VERSION 5.8 ;
BUSBITCHARS "[]" ;
DIVIDERCHAR "/" ;
UNITS
    DATABASE MICRONS 1000 ;
END UNITS

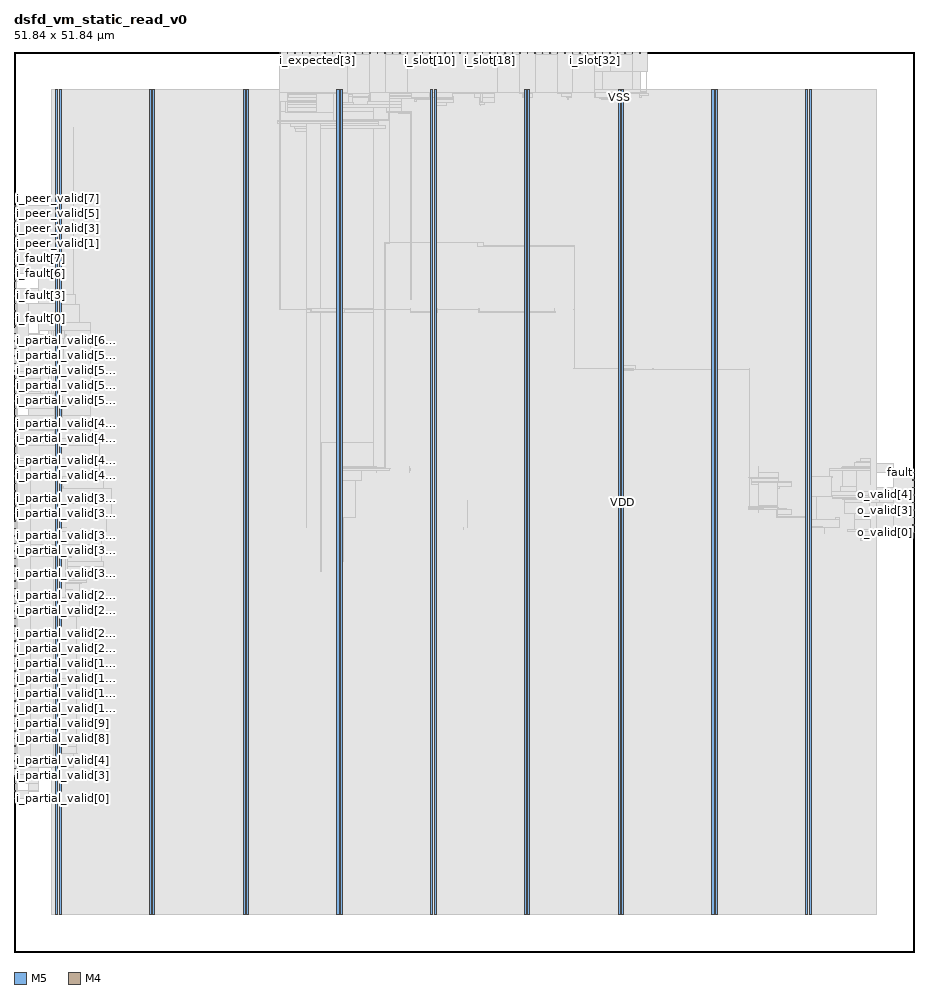
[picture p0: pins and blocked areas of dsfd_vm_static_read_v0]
MACRO dsfd_vm_static_read_v0
  FOREIGN dsfd_vm_static_read_v0 0 0 ;
  CLASS BLOCK ;
  SIZE 51.84 BY 51.84 ;
  PIN ck
    DIRECTION INPUT ;
    USE SIGNAL ;
    PORT
      LAYER M5 ;
        RECT  15.312 51.756 15.336 51.84 ;
    END
  END ck
  PIN fault
    DIRECTION OUTPUT ;
    USE SIGNAL ;
    PORT
      LAYER M4 ;
        RECT  51.756 27.6 51.84 27.624 ;
    END
  END fault
  PIN i_expected[0]
    DIRECTION INPUT ;
    USE SIGNAL ;
    PORT
      LAYER M5 ;
        RECT  16.176 51.756 16.2 51.84 ;
    END
  END i_expected[0]
  PIN i_expected[1]
    DIRECTION INPUT ;
    USE SIGNAL ;
    PORT
      LAYER M5 ;
        RECT  16.608 51.756 16.632 51.84 ;
    END
  END i_expected[1]
  PIN i_expected[2]
    DIRECTION INPUT ;
    USE SIGNAL ;
    PORT
      LAYER M5 ;
        RECT  17.04 51.756 17.064 51.84 ;
    END
  END i_expected[2]
  PIN i_expected[3]
    DIRECTION INPUT ;
    USE SIGNAL ;
    PORT
      LAYER M5 ;
        RECT  17.472 51.756 17.496 51.84 ;
    END
  END i_expected[3]
  PIN i_expected[4]
    DIRECTION INPUT ;
    USE SIGNAL ;
    PORT
      LAYER M5 ;
        RECT  17.904 51.756 17.928 51.84 ;
    END
  END i_expected[4]
  PIN i_expected[5]
    DIRECTION INPUT ;
    USE SIGNAL ;
    PORT
      LAYER M5 ;
        RECT  18.336 51.756 18.36 51.84 ;
    END
  END i_expected[5]
  PIN i_expected[6]
    DIRECTION INPUT ;
    USE SIGNAL ;
    PORT
      LAYER M5 ;
        RECT  18.768 51.756 18.792 51.84 ;
    END
  END i_expected[6]
  PIN i_expected[7]
    DIRECTION INPUT ;
    USE SIGNAL ;
    PORT
      LAYER M5 ;
        RECT  19.2 51.756 19.224 51.84 ;
    END
  END i_expected[7]
  PIN i_fault[0]
    DIRECTION INPUT ;
    USE SIGNAL ;
    PORT
      LAYER M4 ;
        RECT  0 36.48 0.084 36.504 ;
    END
  END i_fault[0]
  PIN i_fault[1]
    DIRECTION INPUT ;
    USE SIGNAL ;
    PORT
      LAYER M4 ;
        RECT  0 36.912 0.084 36.936 ;
    END
  END i_fault[1]
  PIN i_fault[2]
    DIRECTION INPUT ;
    USE SIGNAL ;
    PORT
      LAYER M4 ;
        RECT  0 37.344 0.084 37.368 ;
    END
  END i_fault[2]
  PIN i_fault[3]
    DIRECTION INPUT ;
    USE SIGNAL ;
    PORT
      LAYER M4 ;
        RECT  0 37.776 0.084 37.8 ;
    END
  END i_fault[3]
  PIN i_fault[4]
    DIRECTION INPUT ;
    USE SIGNAL ;
    PORT
      LAYER M4 ;
        RECT  0 38.208 0.084 38.232 ;
    END
  END i_fault[4]
  PIN i_fault[5]
    DIRECTION INPUT ;
    USE SIGNAL ;
    PORT
      LAYER M4 ;
        RECT  0 38.64 0.084 38.664 ;
    END
  END i_fault[5]
  PIN i_fault[6]
    DIRECTION INPUT ;
    USE SIGNAL ;
    PORT
      LAYER M4 ;
        RECT  0 39.072 0.084 39.096 ;
    END
  END i_fault[6]
  PIN i_fault[7]
    DIRECTION INPUT ;
    USE SIGNAL ;
    PORT
      LAYER M4 ;
        RECT  0 39.504 0.084 39.528 ;
    END
  END i_fault[7]
  PIN i_partial_valid[0]
    DIRECTION INPUT ;
    USE SIGNAL ;
    PORT
      LAYER M4 ;
        RECT  0 8.832 0.084 8.856 ;
    END
  END i_partial_valid[0]
  PIN i_partial_valid[10]
    DIRECTION INPUT ;
    USE SIGNAL ;
    PORT
      LAYER M4 ;
        RECT  0 13.152 0.084 13.176 ;
    END
  END i_partial_valid[10]
  PIN i_partial_valid[11]
    DIRECTION INPUT ;
    USE SIGNAL ;
    PORT
      LAYER M4 ;
        RECT  0 13.584 0.084 13.608 ;
    END
  END i_partial_valid[11]
  PIN i_partial_valid[12]
    DIRECTION INPUT ;
    USE SIGNAL ;
    PORT
      LAYER M4 ;
        RECT  0 14.016 0.084 14.04 ;
    END
  END i_partial_valid[12]
  PIN i_partial_valid[13]
    DIRECTION INPUT ;
    USE SIGNAL ;
    PORT
      LAYER M4 ;
        RECT  0 14.448 0.084 14.472 ;
    END
  END i_partial_valid[13]
  PIN i_partial_valid[14]
    DIRECTION INPUT ;
    USE SIGNAL ;
    PORT
      LAYER M4 ;
        RECT  0 14.88 0.084 14.904 ;
    END
  END i_partial_valid[14]
  PIN i_partial_valid[15]
    DIRECTION INPUT ;
    USE SIGNAL ;
    PORT
      LAYER M4 ;
        RECT  0 15.312 0.084 15.336 ;
    END
  END i_partial_valid[15]
  PIN i_partial_valid[16]
    DIRECTION INPUT ;
    USE SIGNAL ;
    PORT
      LAYER M4 ;
        RECT  0 15.744 0.084 15.768 ;
    END
  END i_partial_valid[16]
  PIN i_partial_valid[17]
    DIRECTION INPUT ;
    USE SIGNAL ;
    PORT
      LAYER M4 ;
        RECT  0 16.176 0.084 16.2 ;
    END
  END i_partial_valid[17]
  PIN i_partial_valid[18]
    DIRECTION INPUT ;
    USE SIGNAL ;
    PORT
      LAYER M4 ;
        RECT  0 16.608 0.084 16.632 ;
    END
  END i_partial_valid[18]
  PIN i_partial_valid[19]
    DIRECTION INPUT ;
    USE SIGNAL ;
    PORT
      LAYER M4 ;
        RECT  0 17.04 0.084 17.064 ;
    END
  END i_partial_valid[19]
  PIN i_partial_valid[1]
    DIRECTION INPUT ;
    USE SIGNAL ;
    PORT
      LAYER M4 ;
        RECT  0 9.264 0.084 9.288 ;
    END
  END i_partial_valid[1]
  PIN i_partial_valid[20]
    DIRECTION INPUT ;
    USE SIGNAL ;
    PORT
      LAYER M4 ;
        RECT  0 17.472 0.084 17.496 ;
    END
  END i_partial_valid[20]
  PIN i_partial_valid[21]
    DIRECTION INPUT ;
    USE SIGNAL ;
    PORT
      LAYER M4 ;
        RECT  0 17.904 0.084 17.928 ;
    END
  END i_partial_valid[21]
  PIN i_partial_valid[22]
    DIRECTION INPUT ;
    USE SIGNAL ;
    PORT
      LAYER M4 ;
        RECT  0 18.336 0.084 18.36 ;
    END
  END i_partial_valid[22]
  PIN i_partial_valid[23]
    DIRECTION INPUT ;
    USE SIGNAL ;
    PORT
      LAYER M4 ;
        RECT  0 18.768 0.084 18.792 ;
    END
  END i_partial_valid[23]
  PIN i_partial_valid[24]
    DIRECTION INPUT ;
    USE SIGNAL ;
    PORT
      LAYER M4 ;
        RECT  0 19.2 0.084 19.224 ;
    END
  END i_partial_valid[24]
  PIN i_partial_valid[25]
    DIRECTION INPUT ;
    USE SIGNAL ;
    PORT
      LAYER M4 ;
        RECT  0 19.632 0.084 19.656 ;
    END
  END i_partial_valid[25]
  PIN i_partial_valid[26]
    DIRECTION INPUT ;
    USE SIGNAL ;
    PORT
      LAYER M4 ;
        RECT  0 20.064 0.084 20.088 ;
    END
  END i_partial_valid[26]
  PIN i_partial_valid[27]
    DIRECTION INPUT ;
    USE SIGNAL ;
    PORT
      LAYER M4 ;
        RECT  0 20.496 0.084 20.52 ;
    END
  END i_partial_valid[27]
  PIN i_partial_valid[28]
    DIRECTION INPUT ;
    USE SIGNAL ;
    PORT
      LAYER M4 ;
        RECT  0 20.928 0.084 20.952 ;
    END
  END i_partial_valid[28]
  PIN i_partial_valid[29]
    DIRECTION INPUT ;
    USE SIGNAL ;
    PORT
      LAYER M4 ;
        RECT  0 21.36 0.084 21.384 ;
    END
  END i_partial_valid[29]
  PIN i_partial_valid[2]
    DIRECTION INPUT ;
    USE SIGNAL ;
    PORT
      LAYER M4 ;
        RECT  0 9.696 0.084 9.72 ;
    END
  END i_partial_valid[2]
  PIN i_partial_valid[30]
    DIRECTION INPUT ;
    USE SIGNAL ;
    PORT
      LAYER M4 ;
        RECT  0 21.792 0.084 21.816 ;
    END
  END i_partial_valid[30]
  PIN i_partial_valid[31]
    DIRECTION INPUT ;
    USE SIGNAL ;
    PORT
      LAYER M4 ;
        RECT  0 22.224 0.084 22.248 ;
    END
  END i_partial_valid[31]
  PIN i_partial_valid[32]
    DIRECTION INPUT ;
    USE SIGNAL ;
    PORT
      LAYER M4 ;
        RECT  0 22.656 0.084 22.68 ;
    END
  END i_partial_valid[32]
  PIN i_partial_valid[33]
    DIRECTION INPUT ;
    USE SIGNAL ;
    PORT
      LAYER M4 ;
        RECT  0 23.088 0.084 23.112 ;
    END
  END i_partial_valid[33]
  PIN i_partial_valid[34]
    DIRECTION INPUT ;
    USE SIGNAL ;
    PORT
      LAYER M4 ;
        RECT  0 23.52 0.084 23.544 ;
    END
  END i_partial_valid[34]
  PIN i_partial_valid[35]
    DIRECTION INPUT ;
    USE SIGNAL ;
    PORT
      LAYER M4 ;
        RECT  0 23.952 0.084 23.976 ;
    END
  END i_partial_valid[35]
  PIN i_partial_valid[36]
    DIRECTION INPUT ;
    USE SIGNAL ;
    PORT
      LAYER M4 ;
        RECT  0 24.384 0.084 24.408 ;
    END
  END i_partial_valid[36]
  PIN i_partial_valid[37]
    DIRECTION INPUT ;
    USE SIGNAL ;
    PORT
      LAYER M4 ;
        RECT  0 24.816 0.084 24.84 ;
    END
  END i_partial_valid[37]
  PIN i_partial_valid[38]
    DIRECTION INPUT ;
    USE SIGNAL ;
    PORT
      LAYER M4 ;
        RECT  0 25.248 0.084 25.272 ;
    END
  END i_partial_valid[38]
  PIN i_partial_valid[39]
    DIRECTION INPUT ;
    USE SIGNAL ;
    PORT
      LAYER M4 ;
        RECT  0 25.68 0.084 25.704 ;
    END
  END i_partial_valid[39]
  PIN i_partial_valid[3]
    DIRECTION INPUT ;
    USE SIGNAL ;
    PORT
      LAYER M4 ;
        RECT  0 10.128 0.084 10.152 ;
    END
  END i_partial_valid[3]
  PIN i_partial_valid[40]
    DIRECTION INPUT ;
    USE SIGNAL ;
    PORT
      LAYER M4 ;
        RECT  0 26.112 0.084 26.136 ;
    END
  END i_partial_valid[40]
  PIN i_partial_valid[41]
    DIRECTION INPUT ;
    USE SIGNAL ;
    PORT
      LAYER M4 ;
        RECT  0 26.544 0.084 26.568 ;
    END
  END i_partial_valid[41]
  PIN i_partial_valid[42]
    DIRECTION INPUT ;
    USE SIGNAL ;
    PORT
      LAYER M4 ;
        RECT  0 26.976 0.084 27 ;
    END
  END i_partial_valid[42]
  PIN i_partial_valid[43]
    DIRECTION INPUT ;
    USE SIGNAL ;
    PORT
      LAYER M4 ;
        RECT  0 27.408 0.084 27.432 ;
    END
  END i_partial_valid[43]
  PIN i_partial_valid[44]
    DIRECTION INPUT ;
    USE SIGNAL ;
    PORT
      LAYER M4 ;
        RECT  0 27.84 0.084 27.864 ;
    END
  END i_partial_valid[44]
  PIN i_partial_valid[45]
    DIRECTION INPUT ;
    USE SIGNAL ;
    PORT
      LAYER M4 ;
        RECT  0 28.272 0.084 28.296 ;
    END
  END i_partial_valid[45]
  PIN i_partial_valid[46]
    DIRECTION INPUT ;
    USE SIGNAL ;
    PORT
      LAYER M4 ;
        RECT  0 28.704 0.084 28.728 ;
    END
  END i_partial_valid[46]
  PIN i_partial_valid[47]
    DIRECTION INPUT ;
    USE SIGNAL ;
    PORT
      LAYER M4 ;
        RECT  0 29.136 0.084 29.16 ;
    END
  END i_partial_valid[47]
  PIN i_partial_valid[48]
    DIRECTION INPUT ;
    USE SIGNAL ;
    PORT
      LAYER M4 ;
        RECT  0 29.568 0.084 29.592 ;
    END
  END i_partial_valid[48]
  PIN i_partial_valid[49]
    DIRECTION INPUT ;
    USE SIGNAL ;
    PORT
      LAYER M4 ;
        RECT  0 30 0.084 30.024 ;
    END
  END i_partial_valid[49]
  PIN i_partial_valid[4]
    DIRECTION INPUT ;
    USE SIGNAL ;
    PORT
      LAYER M4 ;
        RECT  0 10.56 0.084 10.584 ;
    END
  END i_partial_valid[4]
  PIN i_partial_valid[50]
    DIRECTION INPUT ;
    USE SIGNAL ;
    PORT
      LAYER M4 ;
        RECT  0 30.432 0.084 30.456 ;
    END
  END i_partial_valid[50]
  PIN i_partial_valid[51]
    DIRECTION INPUT ;
    USE SIGNAL ;
    PORT
      LAYER M4 ;
        RECT  0 30.864 0.084 30.888 ;
    END
  END i_partial_valid[51]
  PIN i_partial_valid[52]
    DIRECTION INPUT ;
    USE SIGNAL ;
    PORT
      LAYER M4 ;
        RECT  0 31.296 0.084 31.32 ;
    END
  END i_partial_valid[52]
  PIN i_partial_valid[53]
    DIRECTION INPUT ;
    USE SIGNAL ;
    PORT
      LAYER M4 ;
        RECT  0 31.728 0.084 31.752 ;
    END
  END i_partial_valid[53]
  PIN i_partial_valid[54]
    DIRECTION INPUT ;
    USE SIGNAL ;
    PORT
      LAYER M4 ;
        RECT  0 32.16 0.084 32.184 ;
    END
  END i_partial_valid[54]
  PIN i_partial_valid[55]
    DIRECTION INPUT ;
    USE SIGNAL ;
    PORT
      LAYER M4 ;
        RECT  0 32.592 0.084 32.616 ;
    END
  END i_partial_valid[55]
  PIN i_partial_valid[56]
    DIRECTION INPUT ;
    USE SIGNAL ;
    PORT
      LAYER M4 ;
        RECT  0 33.024 0.084 33.048 ;
    END
  END i_partial_valid[56]
  PIN i_partial_valid[57]
    DIRECTION INPUT ;
    USE SIGNAL ;
    PORT
      LAYER M4 ;
        RECT  0 33.456 0.084 33.48 ;
    END
  END i_partial_valid[57]
  PIN i_partial_valid[58]
    DIRECTION INPUT ;
    USE SIGNAL ;
    PORT
      LAYER M4 ;
        RECT  0 33.888 0.084 33.912 ;
    END
  END i_partial_valid[58]
  PIN i_partial_valid[59]
    DIRECTION INPUT ;
    USE SIGNAL ;
    PORT
      LAYER M4 ;
        RECT  0 34.32 0.084 34.344 ;
    END
  END i_partial_valid[59]
  PIN i_partial_valid[5]
    DIRECTION INPUT ;
    USE SIGNAL ;
    PORT
      LAYER M4 ;
        RECT  0 10.992 0.084 11.016 ;
    END
  END i_partial_valid[5]
  PIN i_partial_valid[60]
    DIRECTION INPUT ;
    USE SIGNAL ;
    PORT
      LAYER M4 ;
        RECT  0 34.752 0.084 34.776 ;
    END
  END i_partial_valid[60]
  PIN i_partial_valid[61]
    DIRECTION INPUT ;
    USE SIGNAL ;
    PORT
      LAYER M4 ;
        RECT  0 35.184 0.084 35.208 ;
    END
  END i_partial_valid[61]
  PIN i_partial_valid[62]
    DIRECTION INPUT ;
    USE SIGNAL ;
    PORT
      LAYER M4 ;
        RECT  0 35.616 0.084 35.64 ;
    END
  END i_partial_valid[62]
  PIN i_partial_valid[63]
    DIRECTION INPUT ;
    USE SIGNAL ;
    PORT
      LAYER M4 ;
        RECT  0 36.048 0.084 36.072 ;
    END
  END i_partial_valid[63]
  PIN i_partial_valid[6]
    DIRECTION INPUT ;
    USE SIGNAL ;
    PORT
      LAYER M4 ;
        RECT  0 11.424 0.084 11.448 ;
    END
  END i_partial_valid[6]
  PIN i_partial_valid[7]
    DIRECTION INPUT ;
    USE SIGNAL ;
    PORT
      LAYER M4 ;
        RECT  0 11.856 0.084 11.88 ;
    END
  END i_partial_valid[7]
  PIN i_partial_valid[8]
    DIRECTION INPUT ;
    USE SIGNAL ;
    PORT
      LAYER M4 ;
        RECT  0 12.288 0.084 12.312 ;
    END
  END i_partial_valid[8]
  PIN i_partial_valid[9]
    DIRECTION INPUT ;
    USE SIGNAL ;
    PORT
      LAYER M4 ;
        RECT  0 12.72 0.084 12.744 ;
    END
  END i_partial_valid[9]
  PIN i_peer_valid[0]
    DIRECTION INPUT ;
    USE SIGNAL ;
    PORT
      LAYER M4 ;
        RECT  0 39.936 0.084 39.96 ;
    END
  END i_peer_valid[0]
  PIN i_peer_valid[1]
    DIRECTION INPUT ;
    USE SIGNAL ;
    PORT
      LAYER M4 ;
        RECT  0 40.368 0.084 40.392 ;
    END
  END i_peer_valid[1]
  PIN i_peer_valid[2]
    DIRECTION INPUT ;
    USE SIGNAL ;
    PORT
      LAYER M4 ;
        RECT  0 40.8 0.084 40.824 ;
    END
  END i_peer_valid[2]
  PIN i_peer_valid[3]
    DIRECTION INPUT ;
    USE SIGNAL ;
    PORT
      LAYER M4 ;
        RECT  0 41.232 0.084 41.256 ;
    END
  END i_peer_valid[3]
  PIN i_peer_valid[4]
    DIRECTION INPUT ;
    USE SIGNAL ;
    PORT
      LAYER M4 ;
        RECT  0 41.664 0.084 41.688 ;
    END
  END i_peer_valid[4]
  PIN i_peer_valid[5]
    DIRECTION INPUT ;
    USE SIGNAL ;
    PORT
      LAYER M4 ;
        RECT  0 42.096 0.084 42.12 ;
    END
  END i_peer_valid[5]
  PIN i_peer_valid[6]
    DIRECTION INPUT ;
    USE SIGNAL ;
    PORT
      LAYER M4 ;
        RECT  0 42.528 0.084 42.552 ;
    END
  END i_peer_valid[6]
  PIN i_peer_valid[7]
    DIRECTION INPUT ;
    USE SIGNAL ;
    PORT
      LAYER M4 ;
        RECT  0 42.96 0.084 42.984 ;
    END
  END i_peer_valid[7]
  PIN i_slot[0]
    DIRECTION INPUT ;
    USE SIGNAL ;
    PORT
      LAYER M5 ;
        RECT  19.632 51.756 19.656 51.84 ;
    END
  END i_slot[0]
  PIN i_slot[10]
    DIRECTION INPUT ;
    USE SIGNAL ;
    PORT
      LAYER M5 ;
        RECT  23.952 51.756 23.976 51.84 ;
    END
  END i_slot[10]
  PIN i_slot[11]
    DIRECTION INPUT ;
    USE SIGNAL ;
    PORT
      LAYER M5 ;
        RECT  24.384 51.756 24.408 51.84 ;
    END
  END i_slot[11]
  PIN i_slot[12]
    DIRECTION INPUT ;
    USE SIGNAL ;
    PORT
      LAYER M5 ;
        RECT  24.816 51.756 24.84 51.84 ;
    END
  END i_slot[12]
  PIN i_slot[13]
    DIRECTION INPUT ;
    USE SIGNAL ;
    PORT
      LAYER M5 ;
        RECT  25.248 51.756 25.272 51.84 ;
    END
  END i_slot[13]
  PIN i_slot[14]
    DIRECTION INPUT ;
    USE SIGNAL ;
    PORT
      LAYER M5 ;
        RECT  25.68 51.756 25.704 51.84 ;
    END
  END i_slot[14]
  PIN i_slot[15]
    DIRECTION INPUT ;
    USE SIGNAL ;
    PORT
      LAYER M5 ;
        RECT  26.112 51.756 26.136 51.84 ;
    END
  END i_slot[15]
  PIN i_slot[16]
    DIRECTION INPUT ;
    USE SIGNAL ;
    PORT
      LAYER M5 ;
        RECT  26.544 51.756 26.568 51.84 ;
    END
  END i_slot[16]
  PIN i_slot[17]
    DIRECTION INPUT ;
    USE SIGNAL ;
    PORT
      LAYER M5 ;
        RECT  26.976 51.756 27 51.84 ;
    END
  END i_slot[17]
  PIN i_slot[18]
    DIRECTION INPUT ;
    USE SIGNAL ;
    PORT
      LAYER M5 ;
        RECT  27.408 51.756 27.432 51.84 ;
    END
  END i_slot[18]
  PIN i_slot[19]
    DIRECTION INPUT ;
    USE SIGNAL ;
    PORT
      LAYER M5 ;
        RECT  27.84 51.756 27.864 51.84 ;
    END
  END i_slot[19]
  PIN i_slot[1]
    DIRECTION INPUT ;
    USE SIGNAL ;
    PORT
      LAYER M5 ;
        RECT  20.064 51.756 20.088 51.84 ;
    END
  END i_slot[1]
  PIN i_slot[20]
    DIRECTION INPUT ;
    USE SIGNAL ;
    PORT
      LAYER M5 ;
        RECT  28.272 51.756 28.296 51.84 ;
    END
  END i_slot[20]
  PIN i_slot[21]
    DIRECTION INPUT ;
    USE SIGNAL ;
    PORT
      LAYER M5 ;
        RECT  28.704 51.756 28.728 51.84 ;
    END
  END i_slot[21]
  PIN i_slot[22]
    DIRECTION INPUT ;
    USE SIGNAL ;
    PORT
      LAYER M5 ;
        RECT  29.136 51.756 29.16 51.84 ;
    END
  END i_slot[22]
  PIN i_slot[23]
    DIRECTION INPUT ;
    USE SIGNAL ;
    PORT
      LAYER M5 ;
        RECT  29.568 51.756 29.592 51.84 ;
    END
  END i_slot[23]
  PIN i_slot[24]
    DIRECTION INPUT ;
    USE SIGNAL ;
    PORT
      LAYER M5 ;
        RECT  30 51.756 30.024 51.84 ;
    END
  END i_slot[24]
  PIN i_slot[25]
    DIRECTION INPUT ;
    USE SIGNAL ;
    PORT
      LAYER M5 ;
        RECT  30.432 51.756 30.456 51.84 ;
    END
  END i_slot[25]
  PIN i_slot[26]
    DIRECTION INPUT ;
    USE SIGNAL ;
    PORT
      LAYER M5 ;
        RECT  30.864 51.756 30.888 51.84 ;
    END
  END i_slot[26]
  PIN i_slot[27]
    DIRECTION INPUT ;
    USE SIGNAL ;
    PORT
      LAYER M5 ;
        RECT  31.296 51.756 31.32 51.84 ;
    END
  END i_slot[27]
  PIN i_slot[28]
    DIRECTION INPUT ;
    USE SIGNAL ;
    PORT
      LAYER M5 ;
        RECT  31.728 51.756 31.752 51.84 ;
    END
  END i_slot[28]
  PIN i_slot[29]
    DIRECTION INPUT ;
    USE SIGNAL ;
    PORT
      LAYER M5 ;
        RECT  32.16 51.756 32.184 51.84 ;
    END
  END i_slot[29]
  PIN i_slot[2]
    DIRECTION INPUT ;
    USE SIGNAL ;
    PORT
      LAYER M5 ;
        RECT  20.496 51.756 20.52 51.84 ;
    END
  END i_slot[2]
  PIN i_slot[30]
    DIRECTION INPUT ;
    USE SIGNAL ;
    PORT
      LAYER M5 ;
        RECT  32.592 51.756 32.616 51.84 ;
    END
  END i_slot[30]
  PIN i_slot[31]
    DIRECTION INPUT ;
    USE SIGNAL ;
    PORT
      LAYER M5 ;
        RECT  33.024 51.756 33.048 51.84 ;
    END
  END i_slot[31]
  PIN i_slot[32]
    DIRECTION INPUT ;
    USE SIGNAL ;
    PORT
      LAYER M5 ;
        RECT  33.456 51.756 33.48 51.84 ;
    END
  END i_slot[32]
  PIN i_slot[33]
    DIRECTION INPUT ;
    USE SIGNAL ;
    PORT
      LAYER M5 ;
        RECT  33.888 51.756 33.912 51.84 ;
    END
  END i_slot[33]
  PIN i_slot[34]
    DIRECTION INPUT ;
    USE SIGNAL ;
    PORT
      LAYER M5 ;
        RECT  34.32 51.756 34.344 51.84 ;
    END
  END i_slot[34]
  PIN i_slot[35]
    DIRECTION INPUT ;
    USE SIGNAL ;
    PORT
      LAYER M5 ;
        RECT  34.752 51.756 34.776 51.84 ;
    END
  END i_slot[35]
  PIN i_slot[36]
    DIRECTION INPUT ;
    USE SIGNAL ;
    PORT
      LAYER M5 ;
        RECT  35.184 51.756 35.208 51.84 ;
    END
  END i_slot[36]
  PIN i_slot[37]
    DIRECTION INPUT ;
    USE SIGNAL ;
    PORT
      LAYER M5 ;
        RECT  35.616 51.756 35.64 51.84 ;
    END
  END i_slot[37]
  PIN i_slot[38]
    DIRECTION INPUT ;
    USE SIGNAL ;
    PORT
      LAYER M5 ;
        RECT  36.048 51.756 36.072 51.84 ;
    END
  END i_slot[38]
  PIN i_slot[39]
    DIRECTION INPUT ;
    USE SIGNAL ;
    PORT
      LAYER M5 ;
        RECT  36.48 51.756 36.504 51.84 ;
    END
  END i_slot[39]
  PIN i_slot[3]
    DIRECTION INPUT ;
    USE SIGNAL ;
    PORT
      LAYER M5 ;
        RECT  20.928 51.756 20.952 51.84 ;
    END
  END i_slot[3]
  PIN i_slot[4]
    DIRECTION INPUT ;
    USE SIGNAL ;
    PORT
      LAYER M5 ;
        RECT  21.36 51.756 21.384 51.84 ;
    END
  END i_slot[4]
  PIN i_slot[5]
    DIRECTION INPUT ;
    USE SIGNAL ;
    PORT
      LAYER M5 ;
        RECT  21.792 51.756 21.816 51.84 ;
    END
  END i_slot[5]
  PIN i_slot[6]
    DIRECTION INPUT ;
    USE SIGNAL ;
    PORT
      LAYER M5 ;
        RECT  22.224 51.756 22.248 51.84 ;
    END
  END i_slot[6]
  PIN i_slot[7]
    DIRECTION INPUT ;
    USE SIGNAL ;
    PORT
      LAYER M5 ;
        RECT  22.656 51.756 22.68 51.84 ;
    END
  END i_slot[7]
  PIN i_slot[8]
    DIRECTION INPUT ;
    USE SIGNAL ;
    PORT
      LAYER M5 ;
        RECT  23.088 51.756 23.112 51.84 ;
    END
  END i_slot[8]
  PIN i_slot[9]
    DIRECTION INPUT ;
    USE SIGNAL ;
    PORT
      LAYER M5 ;
        RECT  23.52 51.756 23.544 51.84 ;
    END
  END i_slot[9]
  PIN o_valid[0]
    DIRECTION OUTPUT ;
    USE SIGNAL ;
    PORT
      LAYER M4 ;
        RECT  51.756 24.144 51.84 24.168 ;
    END
  END o_valid[0]
  PIN o_valid[1]
    DIRECTION OUTPUT ;
    USE SIGNAL ;
    PORT
      LAYER M4 ;
        RECT  51.756 24.576 51.84 24.6 ;
    END
  END o_valid[1]
  PIN o_valid[2]
    DIRECTION OUTPUT ;
    USE SIGNAL ;
    PORT
      LAYER M4 ;
        RECT  51.756 25.008 51.84 25.032 ;
    END
  END o_valid[2]
  PIN o_valid[3]
    DIRECTION OUTPUT ;
    USE SIGNAL ;
    PORT
      LAYER M4 ;
        RECT  51.756 25.44 51.84 25.464 ;
    END
  END o_valid[3]
  PIN o_valid[4]
    DIRECTION OUTPUT ;
    USE SIGNAL ;
    PORT
      LAYER M4 ;
        RECT  51.756 25.872 51.84 25.896 ;
    END
  END o_valid[4]
  PIN o_valid[5]
    DIRECTION OUTPUT ;
    USE SIGNAL ;
    PORT
      LAYER M4 ;
        RECT  51.756 26.304 51.84 26.328 ;
    END
  END o_valid[5]
  PIN o_valid[6]
    DIRECTION OUTPUT ;
    USE SIGNAL ;
    PORT
      LAYER M4 ;
        RECT  51.756 26.736 51.84 26.76 ;
    END
  END o_valid[6]
  PIN o_valid[7]
    DIRECTION OUTPUT ;
    USE SIGNAL ;
    PORT
      LAYER M4 ;
        RECT  51.756 27.168 51.84 27.192 ;
    END
  END o_valid[7]
  PIN rst_n
    DIRECTION INPUT ;
    USE SIGNAL ;
    PORT
      LAYER M5 ;
        RECT  15.744 51.756 15.768 51.84 ;
    END
  END rst_n
  PIN VDD
    DIRECTION INOUT ;
    USE POWER ;
    PORT
      LAYER M5 ;
        RECT  45.792 2.151 45.912 49.689 ;
        RECT  40.392 2.151 40.512 49.689 ;
        RECT  34.992 2.151 35.112 49.689 ;
        RECT  29.592 2.151 29.712 49.689 ;
        RECT  24.192 2.151 24.312 49.689 ;
        RECT  18.792 2.151 18.912 49.689 ;
        RECT  13.392 2.151 13.512 49.689 ;
        RECT  7.992 2.151 8.112 49.689 ;
        RECT  2.592 2.151 2.712 49.689 ;
    END
  END VDD
  PIN VSS
    DIRECTION INOUT ;
    USE GROUND ;
    PORT
      LAYER M5 ;
        RECT  45.6 2.137 45.72 49.703 ;
        RECT  40.2 2.137 40.32 49.703 ;
        RECT  34.8 2.137 34.92 49.703 ;
        RECT  29.4 2.137 29.52 49.703 ;
        RECT  24 2.137 24.12 49.703 ;
        RECT  18.6 2.137 18.72 49.703 ;
        RECT  13.2 2.137 13.32 49.703 ;
        RECT  7.8 2.137 7.92 49.703 ;
        RECT  2.4 2.137 2.52 49.703 ;
    END
  END VSS
  # OT_OBS_CLOSED layer=M5 d_um=1.536 added=32
  OBS
    LAYER RVTN ;
     RECT  2.16 2.16 49.68 2.295 ;
     RECT  2.16 2.565 49.68 2.835 ;
     RECT  2.16 3.105 49.68 3.375 ;
     RECT  2.16 3.645 49.68 3.915 ;
     RECT  2.16 4.185 49.68 4.455 ;
     RECT  2.16 4.725 49.68 4.995 ;
     RECT  2.16 5.265 49.68 5.535 ;
     RECT  2.16 5.805 49.68 6.075 ;
     RECT  2.16 6.345 49.68 6.615 ;
     RECT  2.16 6.885 49.68 7.155 ;
     RECT  2.16 7.425 49.68 7.695 ;
     RECT  2.16 7.965 49.68 8.235 ;
     RECT  2.16 8.505 49.68 8.775 ;
     RECT  2.16 9.045 49.68 9.315 ;
     RECT  2.16 9.585 49.68 9.855 ;
     RECT  2.16 10.125 49.68 10.395 ;
     RECT  2.16 10.665 49.68 10.935 ;
     RECT  2.16 11.205 49.68 11.475 ;
     RECT  2.16 11.745 49.68 12.015 ;
     RECT  2.16 12.285 49.68 12.555 ;
     RECT  2.16 12.825 49.68 13.095 ;
     RECT  2.16 13.365 49.68 13.635 ;
     RECT  2.16 13.905 49.68 14.175 ;
     RECT  2.16 14.445 49.68 14.715 ;
     RECT  2.16 14.985 49.68 15.255 ;
     RECT  2.16 15.525 49.68 15.795 ;
     RECT  2.16 16.065 49.68 16.335 ;
     RECT  2.16 16.605 49.68 16.875 ;
     RECT  2.16 17.145 49.68 17.415 ;
     RECT  2.16 17.685 49.68 17.955 ;
     RECT  2.16 18.225 49.68 18.495 ;
     RECT  2.16 18.765 49.68 19.035 ;
     RECT  2.16 19.305 49.68 19.575 ;
     RECT  2.16 19.845 49.68 20.115 ;
     RECT  2.16 20.385 49.68 20.655 ;
     RECT  2.16 20.925 49.68 21.195 ;
     RECT  2.16 21.465 49.68 21.735 ;
     RECT  2.16 22.005 49.68 22.275 ;
     RECT  2.16 22.545 49.68 22.815 ;
     RECT  2.16 23.085 49.68 23.355 ;
     RECT  2.16 23.625 49.68 23.895 ;
     RECT  2.16 24.165 49.68 24.435 ;
     RECT  2.16 24.705 49.68 24.975 ;
     RECT  2.16 25.245 49.68 25.515 ;
     RECT  2.16 25.785 49.68 26.055 ;
     RECT  2.16 26.325 49.68 26.595 ;
     RECT  2.16 26.865 49.68 27.135 ;
     RECT  2.16 27.405 49.68 27.675 ;
     RECT  2.16 27.945 49.68 28.215 ;
     RECT  2.16 28.485 49.68 28.755 ;
     RECT  2.16 29.025 49.68 29.295 ;
     RECT  2.16 29.565 49.68 29.835 ;
     RECT  2.16 30.105 49.68 30.375 ;
     RECT  2.16 30.645 49.68 30.915 ;
     RECT  2.16 31.185 49.68 31.455 ;
     RECT  2.16 31.725 49.68 31.995 ;
     RECT  2.16 32.265 49.68 32.535 ;
     RECT  2.16 32.805 49.68 33.075 ;
     RECT  2.16 33.345 49.68 33.615 ;
     RECT  2.16 33.885 49.68 34.155 ;
     RECT  2.16 34.425 49.68 34.695 ;
     RECT  2.16 34.965 49.68 35.235 ;
     RECT  2.16 35.505 49.68 35.775 ;
     RECT  2.16 36.045 49.68 36.315 ;
     RECT  2.16 36.585 49.68 36.855 ;
     RECT  2.16 37.125 49.68 37.395 ;
     RECT  2.16 37.665 49.68 37.935 ;
     RECT  2.16 38.205 49.68 38.475 ;
     RECT  2.16 38.745 49.68 39.015 ;
     RECT  2.16 39.285 49.68 39.555 ;
     RECT  2.16 39.825 49.68 40.095 ;
     RECT  2.16 40.365 49.68 40.635 ;
     RECT  2.16 40.905 49.68 41.175 ;
     RECT  2.16 41.445 49.68 41.715 ;
     RECT  2.16 41.985 49.68 42.255 ;
     RECT  2.16 42.525 49.68 42.795 ;
     RECT  2.16 43.065 49.68 43.335 ;
     RECT  2.16 43.605 49.68 43.875 ;
     RECT  2.16 44.145 49.68 44.415 ;
     RECT  2.16 44.685 49.68 44.955 ;
     RECT  2.16 45.225 49.68 45.495 ;
     RECT  2.16 45.765 49.68 46.035 ;
     RECT  2.16 46.305 49.68 46.575 ;
     RECT  2.16 46.845 49.68 47.115 ;
     RECT  2.16 47.385 49.68 47.655 ;
     RECT  2.16 47.925 49.68 48.195 ;
     RECT  2.16 48.465 49.68 48.735 ;
     RECT  2.16 49.005 49.68 49.275 ;
     RECT  2.16 49.545 49.68 49.68 ;
    LAYER RVTP ;
     RECT  2.16 2.295 49.68 2.565 ;
     RECT  2.16 2.835 49.68 3.105 ;
     RECT  2.16 3.375 49.68 3.645 ;
     RECT  2.16 3.915 49.68 4.185 ;
     RECT  2.16 4.455 49.68 4.725 ;
     RECT  2.16 4.995 49.68 5.265 ;
     RECT  2.16 5.535 49.68 5.805 ;
     RECT  2.16 6.075 49.68 6.345 ;
     RECT  2.16 6.615 49.68 6.885 ;
     RECT  2.16 7.155 49.68 7.425 ;
     RECT  2.16 7.695 49.68 7.965 ;
     RECT  2.16 8.235 49.68 8.505 ;
     RECT  2.16 8.775 49.68 9.045 ;
     RECT  2.16 9.315 49.68 9.585 ;
     RECT  2.16 9.855 49.68 10.125 ;
     RECT  2.16 10.395 49.68 10.665 ;
     RECT  2.16 10.935 49.68 11.205 ;
     RECT  2.16 11.475 49.68 11.745 ;
     RECT  2.16 12.015 49.68 12.285 ;
     RECT  2.16 12.555 49.68 12.825 ;
     RECT  2.16 13.095 49.68 13.365 ;
     RECT  2.16 13.635 49.68 13.905 ;
     RECT  2.16 14.175 49.68 14.445 ;
     RECT  2.16 14.715 49.68 14.985 ;
     RECT  2.16 15.255 49.68 15.525 ;
     RECT  2.16 15.795 49.68 16.065 ;
     RECT  2.16 16.335 49.68 16.605 ;
     RECT  2.16 16.875 49.68 17.145 ;
     RECT  2.16 17.415 49.68 17.685 ;
     RECT  2.16 17.955 49.68 18.225 ;
     RECT  2.16 18.495 49.68 18.765 ;
     RECT  2.16 19.035 49.68 19.305 ;
     RECT  2.16 19.575 49.68 19.845 ;
     RECT  2.16 20.115 49.68 20.385 ;
     RECT  2.16 20.655 49.68 20.925 ;
     RECT  2.16 21.195 49.68 21.465 ;
     RECT  2.16 21.735 49.68 22.005 ;
     RECT  2.16 22.275 49.68 22.545 ;
     RECT  2.16 22.815 49.68 23.085 ;
     RECT  2.16 23.355 49.68 23.625 ;
     RECT  2.16 23.895 49.68 24.165 ;
     RECT  2.16 24.435 49.68 24.705 ;
     RECT  2.16 24.975 49.68 25.245 ;
     RECT  2.16 25.515 49.68 25.785 ;
     RECT  2.16 26.055 49.68 26.325 ;
     RECT  2.16 26.595 49.68 26.865 ;
     RECT  2.16 27.135 49.68 27.405 ;
     RECT  2.16 27.675 49.68 27.945 ;
     RECT  2.16 28.215 49.68 28.485 ;
     RECT  2.16 28.755 49.68 29.025 ;
     RECT  2.16 29.295 49.68 29.565 ;
     RECT  2.16 29.835 49.68 30.105 ;
     RECT  2.16 30.375 49.68 30.645 ;
     RECT  2.16 30.915 49.68 31.185 ;
     RECT  2.16 31.455 49.68 31.725 ;
     RECT  2.16 31.995 49.68 32.265 ;
     RECT  2.16 32.535 49.68 32.805 ;
     RECT  2.16 33.075 49.68 33.345 ;
     RECT  2.16 33.615 49.68 33.885 ;
     RECT  2.16 34.155 49.68 34.425 ;
     RECT  2.16 34.695 49.68 34.965 ;
     RECT  2.16 35.235 49.68 35.505 ;
     RECT  2.16 35.775 49.68 36.045 ;
     RECT  2.16 36.315 49.68 36.585 ;
     RECT  2.16 36.855 49.68 37.125 ;
     RECT  2.16 37.395 49.68 37.665 ;
     RECT  2.16 37.935 49.68 38.205 ;
     RECT  2.16 38.475 49.68 38.745 ;
     RECT  2.16 39.015 49.68 39.285 ;
     RECT  2.16 39.555 49.68 39.825 ;
     RECT  2.16 40.095 49.68 40.365 ;
     RECT  2.16 40.635 49.68 40.905 ;
     RECT  2.16 41.175 49.68 41.445 ;
     RECT  2.16 41.715 49.68 41.985 ;
     RECT  2.16 42.255 49.68 42.525 ;
     RECT  2.16 42.795 49.68 43.065 ;
     RECT  2.16 43.335 49.68 43.605 ;
     RECT  2.16 43.875 49.68 44.145 ;
     RECT  2.16 44.415 49.68 44.685 ;
     RECT  2.16 44.955 49.68 45.225 ;
     RECT  2.16 45.495 49.68 45.765 ;
     RECT  2.16 46.035 49.68 46.305 ;
     RECT  2.16 46.575 49.68 46.845 ;
     RECT  2.16 47.115 49.68 47.385 ;
     RECT  2.16 47.655 49.68 47.925 ;
     RECT  2.16 48.195 49.68 48.465 ;
     RECT  2.16 48.735 49.68 49.005 ;
     RECT  2.16 49.275 49.68 49.545 ;
    LAYER M1 ;
     RECT  2.16 2.151 49.68 49.689 ;
    LAYER M2 ;
     RECT  0.031 24.714 0.067 24.732 ;
     RECT  0.031 33.282 0.103 33.3 ;
     RECT  0.103 28.422 0.139 28.44 ;
     RECT  0.103 30.15 0.139 30.168 ;
     RECT  0.103 37.602 0.139 37.998 ;
     RECT  0.103 14.841 0.203 14.859 ;
     RECT  0.103 18.504 0.203 18.828 ;
     RECT  0.103 23.292 0.823 23.31 ;
     RECT  0.103 27.342 0.859 27.36 ;
     RECT  0.139 28.422 0.895 28.71 ;
     RECT  0.103 32.31 0.931 32.328 ;
     RECT  0.103 33.282 0.931 33.84 ;
     RECT  0.823 23.292 1.147 23.454 ;
     RECT  0.067 24.246 1.147 24.732 ;
     RECT  0.139 30.078 1.147 30.168 ;
     RECT  0.931 32.31 1.399 33.84 ;
     RECT  1.399 32.31 1.435 33.912 ;
     RECT  0.895 28.422 1.471 28.782 ;
     RECT  0.139 37.602 1.471 38.196 ;
     RECT  0.103 39.222 1.471 39.24 ;
     RECT  1.399 36.36 1.507 36.378 ;
     RECT  1.435 31.734 1.543 33.912 ;
     RECT  1.435 35.55 1.975 35.568 ;
     RECT  1.507 36.36 1.975 36.648 ;
     RECT  1.543 31.662 2.011 33.912 ;
     RECT  0.823 25.866 2.047 25.884 ;
     RECT  2.047 25.758 2.119 25.884 ;
     RECT  0.859 26.802 2.119 27.36 ;
     RECT  1.147 23.292 2.155 24.732 ;
     RECT  2.119 25.758 2.155 27.36 ;
     RECT  1.723 15.462 2.16 15.48 ;
     RECT  1.507 18.162 2.16 18.18 ;
     RECT  1.543 19.782 2.16 19.8 ;
     RECT  0.175 21.366 2.16 21.384 ;
     RECT  0.103 22.212 2.16 22.23 ;
     RECT  2.155 23.292 2.16 27.36 ;
     RECT  1.471 28.422 2.16 28.98 ;
     RECT  1.147 29.772 2.16 30.168 ;
     RECT  2.011 31.392 2.16 33.912 ;
     RECT  1.975 35.55 2.16 36.648 ;
     RECT  1.471 37.602 2.16 39.24 ;
     RECT  2.16 2.151 49.68 49.689 ;
     RECT  49.68 27.612 50.675 28.134 ;
     RECT  49.68 24.138 50.711 26.784 ;
     RECT  50.675 27.612 50.711 27.63 ;
     RECT  50.711 24.48 50.747 24.498 ;
     RECT  50.711 26.064 50.747 26.082 ;
    LAYER M3 ;
     RECT  2.415 2.143 2.505 2.413 ;
     RECT  7.815 2.143 7.905 2.413 ;
     RECT  13.215 2.143 13.305 2.413 ;
     RECT  18.615 2.143 18.705 2.413 ;
     RECT  24.015 2.143 24.105 2.413 ;
     RECT  29.415 2.143 29.505 2.413 ;
     RECT  34.815 2.143 34.905 2.413 ;
     RECT  40.215 2.143 40.305 2.413 ;
     RECT  45.615 2.143 45.705 2.413 ;
     RECT  0.828 8.827 0.846 9.259 ;
     RECT  0.828 9.259 1.422 9.691 ;
     RECT  0.108 9.691 1.422 10.219 ;
     RECT  2.415 2.413 2.697 10.651 ;
     RECT  2.415 10.651 3.402 10.987 ;
     RECT  2.415 10.987 3.438 11.419 ;
     RECT  0.036 10.219 1.422 11.851 ;
     RECT  2.415 11.419 3.618 11.851 ;
     RECT  0.036 11.851 3.618 19.345 ;
     RECT  0.036 19.345 3.798 21.235 ;
     RECT  0.036 21.235 3.906 21.271 ;
     RECT  0.036 21.271 4.158 21.389 ;
     RECT  0.828 21.389 4.158 21.541 ;
     RECT  0.828 21.541 4.59 21.811 ;
     RECT  0.036 21.389 0.054 22.207 ;
     RECT  0.828 21.811 5.13 22.207 ;
     RECT  18.615 2.413 18.897 22.477 ;
     RECT  0.036 22.207 5.13 22.505 ;
     RECT  0.036 22.505 5.022 23.459 ;
     RECT  0.036 23.459 0.126 23.549 ;
     RECT  48.744 23.701 49.05 23.791 ;
     RECT  48.744 23.791 49.122 23.935 ;
     RECT  48.636 23.935 49.122 23.971 ;
     RECT  0.864 23.459 5.022 24.241 ;
     RECT  48.636 23.971 49.338 24.241 ;
     RECT  47.988 24.241 49.338 24.359 ;
     RECT  0.036 23.549 0.09 24.379 ;
     RECT  25.884 24.331 25.902 24.431 ;
     RECT  46.692 24.097 46.71 24.439 ;
     RECT  45.615 2.413 45.897 24.475 ;
     RECT  46.692 24.439 47.538 24.475 ;
     RECT  50.688 24.133 50.706 24.475 ;
     RECT  50.688 24.475 50.742 24.605 ;
     RECT  0.036 24.379 0.126 24.737 ;
     RECT  48.42 24.359 49.338 24.899 ;
     RECT  45.576 24.475 47.538 24.935 ;
     RECT  47.304 24.935 47.538 25.007 ;
     RECT  0.864 24.241 5.31 25.015 ;
     RECT  18.615 22.477 18.954 25.051 ;
     RECT  43.956 25.051 43.974 25.213 ;
     RECT  44.748 25.177 44.766 25.213 ;
     RECT  48.42 24.899 49.302 25.285 ;
     RECT  50.688 24.605 50.706 25.469 ;
     RECT  43.956 25.213 44.766 25.475 ;
     RECT  42.876 25.321 42.894 25.483 ;
     RECT  43.956 25.475 44.514 25.547 ;
     RECT  42.336 25.483 42.894 25.555 ;
     RECT  42.336 25.555 43.182 25.591 ;
     RECT  43.956 25.547 44.01 25.591 ;
     RECT  42.336 25.591 44.01 25.619 ;
     RECT  42.336 25.619 43.974 25.661 ;
     RECT  42.876 25.661 43.974 25.709 ;
     RECT  43.704 25.709 43.974 25.745 ;
     RECT  0.072 24.737 0.126 25.861 ;
     RECT  0.864 25.015 5.634 25.861 ;
     RECT  47.808 25.285 49.302 25.867 ;
     RECT  26.1 24.475 26.118 25.979 ;
     RECT  47.808 25.867 49.842 26.059 ;
     RECT  47.736 26.059 49.842 26.095 ;
     RECT  47.124 26.095 49.842 26.159 ;
     RECT  45.576 24.935 46.206 26.257 ;
     RECT  45.576 26.257 46.386 26.285 ;
     RECT  45.615 26.285 46.386 26.293 ;
     RECT  47.124 26.159 49.194 26.293 ;
     RECT  50.724 26.059 50.742 26.333 ;
     RECT  45.615 26.293 49.194 26.519 ;
     RECT  45.615 26.519 46.854 26.555 ;
     RECT  43.956 25.745 43.974 26.671 ;
     RECT  0.072 25.861 5.634 26.699 ;
     RECT  47.592 26.519 48.546 26.789 ;
     RECT  50.688 26.731 50.706 26.789 ;
     RECT  43.956 26.671 44.118 26.797 ;
     RECT  42.876 25.709 42.894 26.941 ;
     RECT  42.48 26.941 42.894 27.031 ;
     RECT  43.956 26.797 44.766 27.031 ;
     RECT  42.48 27.031 44.766 27.095 ;
     RECT  18.615 25.051 19.674 27.175 ;
     RECT  0.072 26.699 5.13 27.203 ;
     RECT  42.48 27.095 44.046 27.301 ;
     RECT  42.336 27.301 44.046 27.341 ;
     RECT  0.072 27.203 4.95 27.365 ;
     RECT  50.652 27.163 50.67 27.595 ;
     RECT  42.876 27.341 44.046 27.599 ;
     RECT  42.876 27.599 43.83 27.635 ;
     RECT  50.652 27.595 50.706 27.635 ;
     RECT  20.88 27.643 20.898 27.715 ;
     RECT  22.788 27.643 22.806 27.715 ;
     RECT  46.98 27.355 46.998 27.715 ;
     RECT  47.736 26.789 48.51 27.715 ;
     RECT  18.615 27.175 19.998 27.751 ;
     RECT  20.88 27.715 21.618 27.751 ;
     RECT  46.98 27.715 48.546 27.751 ;
     RECT  49.32 26.905 49.338 27.751 ;
     RECT  18.615 27.751 21.618 27.832 ;
     RECT  18.615 27.832 21.69 27.869 ;
     RECT  22.788 27.715 22.842 27.869 ;
     RECT  46.98 27.751 49.338 27.869 ;
     RECT  18.615 27.869 21.294 27.905 ;
     RECT  47.664 27.869 49.338 27.905 ;
     RECT  18.615 27.905 20.898 27.941 ;
     RECT  22.788 27.869 22.806 27.941 ;
     RECT  42.876 27.635 42.894 27.941 ;
     RECT  47.736 27.905 49.338 27.941 ;
     RECT  50.652 27.635 50.67 28.139 ;
     RECT  48.42 27.941 49.338 28.175 ;
     RECT  48.528 28.175 49.338 28.247 ;
     RECT  48.744 28.247 49.338 28.409 ;
     RECT  0.072 27.365 0.09 28.417 ;
     RECT  0.828 27.365 4.95 28.417 ;
     RECT  0.072 28.417 4.95 29.165 ;
     RECT  0.828 29.165 4.95 29.335 ;
     RECT  17.676 21.937 17.694 29.335 ;
     RECT  18.615 27.941 20.682 29.335 ;
     RECT  0.828 29.335 5.13 29.561 ;
     RECT  0.072 29.165 0.09 30.073 ;
     RECT  0.828 29.561 4.41 30.073 ;
     RECT  0.072 30.073 4.41 30.893 ;
     RECT  0.828 30.893 4.41 31.487 ;
     RECT  0.828 31.487 1.566 31.685 ;
     RECT  0.072 30.893 0.09 32.305 ;
     RECT  0.828 31.685 1.53 32.305 ;
     RECT  0.072 32.305 1.53 33.053 ;
     RECT  34.815 2.413 35.097 33.511 ;
     RECT  34.815 33.511 35.694 33.547 ;
     RECT  36.792 33.541 36.81 33.581 ;
     RECT  34.815 33.547 35.802 33.809 ;
     RECT  0.036 33.277 0.054 33.817 ;
     RECT  0.828 33.053 1.53 33.817 ;
     RECT  0.036 33.817 1.53 33.917 ;
     RECT  0.036 33.917 0.846 34.781 ;
     RECT  0.828 34.781 0.846 35.545 ;
     RECT  0.828 35.545 1.458 35.645 ;
     RECT  1.404 35.645 1.458 35.815 ;
     RECT  2.304 31.487 4.41 35.815 ;
     RECT  0.036 34.781 0.054 35.899 ;
     RECT  0.036 35.899 0.126 35.933 ;
     RECT  0.108 35.933 0.126 36.077 ;
     RECT  1.404 35.815 4.41 36.239 ;
     RECT  16.848 24.439 16.866 36.859 ;
     RECT  17.676 29.335 20.682 36.859 ;
     RECT  24.015 2.413 24.297 36.859 ;
     RECT  16.848 36.859 20.682 37.037 ;
     RECT  22.824 36.859 22.842 37.037 ;
     RECT  24.015 36.859 24.39 37.037 ;
     RECT  26.784 36.859 26.802 37.037 ;
     RECT  31.14 36.859 31.158 37.049 ;
     RECT  32.256 37.003 32.274 37.121 ;
     RECT  1.404 36.239 3.762 37.319 ;
     RECT  1.404 37.319 3.546 37.859 ;
     RECT  0.108 37.597 0.126 38.173 ;
     RECT  0.108 38.173 0.162 38.237 ;
     RECT  0.144 38.237 0.162 38.669 ;
     RECT  0.108 39.217 0.126 39.533 ;
     RECT  1.404 37.859 3.438 40.559 ;
     RECT  26.712 40.651 26.73 40.801 ;
     RECT  26.712 40.801 27.018 40.829 ;
     RECT  27 40.829 27.018 40.877 ;
     RECT  1.404 40.559 2.697 41.261 ;
     RECT  1.476 41.261 2.697 42.557 ;
     RECT  1.476 42.557 1.494 42.989 ;
     RECT  16.848 37.037 16.866 47.281 ;
     RECT  16.2 47.281 16.866 47.425 ;
     RECT  17.676 37.037 20.682 47.461 ;
     RECT  3.42 40.559 3.438 47.489 ;
     RECT  16.128 47.425 16.866 47.551 ;
     RECT  17.676 47.461 21.402 47.579 ;
     RECT  15.912 47.551 16.866 47.695 ;
     RECT  17.676 47.579 20.97 47.695 ;
     RECT  15.156 47.695 20.97 47.849 ;
     RECT  15.156 47.849 20.682 47.885 ;
     RECT  22.86 37.597 22.878 48.271 ;
     RECT  22.14 48.271 22.878 48.331 ;
     RECT  15.3 47.885 20.682 48.389 ;
     RECT  21.456 48.331 22.878 48.389 ;
     RECT  15.624 48.389 20.682 48.667 ;
     RECT  21.456 48.389 22.338 48.667 ;
     RECT  24.015 37.037 24.297 48.775 ;
     RECT  26.856 48.739 26.874 48.811 ;
     RECT  15.624 48.667 22.338 48.839 ;
     RECT  15.624 48.839 19.566 48.929 ;
     RECT  24.015 48.775 24.894 48.937 ;
     RECT  26.82 48.811 27.09 48.937 ;
     RECT  15.624 48.929 19.494 48.965 ;
     RECT  20.376 48.839 22.338 48.965 ;
     RECT  23.076 48.973 23.094 49.009 ;
     RECT  15.66 48.965 19.494 49.037 ;
     RECT  23.076 49.009 23.202 49.081 ;
     RECT  24.015 48.937 25.29 49.081 ;
     RECT  34.815 33.809 35.097 49.081 ;
     RECT  20.412 48.965 22.338 49.171 ;
     RECT  23.076 49.081 25.29 49.171 ;
     RECT  33.84 49.081 35.097 49.171 ;
     RECT  29.415 2.413 29.697 49.207 ;
     RECT  31.896 49.081 31.914 49.207 ;
     RECT  33.696 49.171 35.097 49.207 ;
     RECT  15.768 49.037 19.494 49.235 ;
     RECT  26.82 48.937 27.666 49.243 ;
     RECT  29.268 49.207 29.697 49.243 ;
     RECT  31.824 49.207 31.914 49.243 ;
     RECT  20.412 49.171 25.29 49.277 ;
     RECT  33.516 49.207 35.097 49.277 ;
     RECT  31.824 49.243 32.13 49.279 ;
     RECT  20.412 49.277 24.894 49.307 ;
     RECT  33.696 49.277 35.097 49.307 ;
     RECT  36 49.207 36.126 49.351 ;
     RECT  15.804 49.235 19.494 49.379 ;
     RECT  2.415 42.557 2.697 49.427 ;
     RECT  7.815 2.413 8.097 49.427 ;
     RECT  13.215 2.413 13.497 49.427 ;
     RECT  33.768 49.307 35.097 49.427 ;
     RECT  40.215 2.413 40.497 49.427 ;
     RECT  45.615 26.555 45.897 49.427 ;
     RECT  15.912 49.379 19.494 49.469 ;
     RECT  20.556 49.307 24.894 49.469 ;
     RECT  26.532 49.243 27.666 49.469 ;
     RECT  29.268 49.243 29.862 49.469 ;
     RECT  31.536 49.279 32.13 49.469 ;
     RECT  36 49.351 36.558 49.469 ;
     RECT  29.268 49.469 29.754 49.477 ;
     RECT  31.536 49.469 32.022 49.477 ;
     RECT  36 49.469 36.45 49.477 ;
     RECT  15.984 49.469 19.494 49.505 ;
     RECT  26.532 49.469 27.522 49.517 ;
     RECT  29.196 49.477 29.754 49.517 ;
     RECT  31.32 49.477 32.022 49.517 ;
     RECT  35.676 49.477 36.45 49.517 ;
     RECT  20.556 49.469 24.57 49.541 ;
     RECT  20.556 49.541 21.33 49.565 ;
     RECT  22.284 49.541 24.57 49.565 ;
     RECT  29.415 49.517 29.754 49.565 ;
     RECT  31.608 49.517 32.022 49.565 ;
     RECT  16.164 49.505 19.494 49.577 ;
     RECT  20.556 49.565 20.574 49.577 ;
     RECT  23.148 49.565 24.105 49.577 ;
     RECT  25.668 49.531 26.226 49.577 ;
     RECT  27.18 49.517 27.522 49.577 ;
     RECT  31.608 49.565 31.626 49.577 ;
     RECT  33.768 49.427 34.905 49.577 ;
     RECT  35.928 49.517 36.45 49.577 ;
     RECT  2.415 49.427 2.505 49.697 ;
     RECT  7.815 49.427 7.905 49.697 ;
     RECT  13.215 49.427 13.305 49.697 ;
     RECT  18.615 49.577 18.81 49.697 ;
     RECT  23.976 49.577 24.105 49.697 ;
     RECT  29.415 49.565 29.574 49.697 ;
     RECT  34.164 49.577 34.905 49.697 ;
     RECT  40.215 49.427 40.305 49.697 ;
     RECT  45.615 49.427 45.705 49.697 ;
     RECT  18.792 49.697 18.81 49.805 ;
     RECT  29.556 49.697 29.574 49.805 ;
     RECT  23.976 49.697 23.994 49.853 ;
     RECT  27.18 49.577 27.198 50.189 ;
     RECT  34.164 49.697 34.182 50.765 ;
     RECT  36.432 49.577 36.45 50.765 ;
    LAYER M4 ;
     RECT  0.025 10.224 0.06 10.248 ;
     RECT  0.025 35.904 0.06 35.928 ;
     RECT  0.06 8.832 0.137 42.984 ;
     RECT  0.137 8.832 0.173 37.368 ;
     RECT  0.137 38.64 0.173 42.984 ;
     RECT  0.173 8.832 0.857 9.288 ;
     RECT  0.173 33.456 0.857 37.368 ;
     RECT  0.173 10.656 0.965 28.296 ;
     RECT  0.857 9.264 1.433 9.288 ;
     RECT  0.965 10.656 2.257 22.776 ;
     RECT  0.173 29.568 2.329 30.024 ;
     RECT  0.173 31.296 2.329 32.184 ;
     RECT  2.257 10.656 2.408 22.824 ;
     RECT  0.965 23.952 2.408 28.296 ;
     RECT  2.329 29.568 2.408 32.184 ;
     RECT  0.857 33.456 2.408 35.208 ;
     RECT  0.857 36.48 2.408 37.368 ;
     RECT  0.173 39.072 2.408 42.984 ;
     RECT  2.408 2.148 2.512 49.692 ;
     RECT  2.512 2.418 2.704 49.422 ;
     RECT  2.704 26.784 2.801 27.384 ;
     RECT  2.704 30.816 2.819 31.992 ;
     RECT  2.801 26.784 2.837 26.808 ;
     RECT  2.819 31.728 2.837 31.752 ;
     RECT  2.704 34.08 2.837 35.784 ;
     RECT  2.837 35.376 2.915 35.784 ;
     RECT  2.704 20.4 2.945 22.776 ;
     RECT  2.915 35.376 2.956 35.592 ;
     RECT  2.945 20.4 2.981 20.904 ;
     RECT  2.704 24.432 3.017 24.456 ;
     RECT  2.956 35.424 3.017 35.592 ;
     RECT  2.945 21.936 3.089 22.776 ;
     RECT  2.837 34.08 3.125 34.152 ;
     RECT  3.017 35.424 3.161 35.448 ;
     RECT  3.089 22.752 3.305 22.776 ;
     RECT  2.704 15.744 3.341 15.768 ;
     RECT  3.125 34.128 3.341 34.152 ;
     RECT  2.981 20.88 3.377 20.904 ;
     RECT  2.704 10.656 3.413 11.448 ;
     RECT  3.413 10.992 3.449 11.448 ;
     RECT  3.449 11.424 3.629 11.448 ;
     RECT  3.805 24.384 3.989 24.408 ;
     RECT  4.237 25.056 4.349 25.08 ;
     RECT  7.808 2.148 7.912 49.692 ;
     RECT  7.912 2.418 8.104 49.422 ;
     RECT  13.208 2.148 13.312 49.692 ;
     RECT  13.312 2.418 13.504 49.422 ;
     RECT  15.613 48.384 15.649 48.408 ;
     RECT  15.649 48.384 15.779 49.032 ;
     RECT  16.124 49.536 17.029 49.56 ;
     RECT  15.301 37.008 17.089 37.032 ;
     RECT  17.089 36.864 17.129 37.032 ;
     RECT  15.779 48.384 17.449 48.408 ;
     RECT  17.029 49.488 17.449 49.56 ;
     RECT  17.449 48.384 18.385 49.56 ;
     RECT  17.129 36.864 18.608 36.888 ;
     RECT  18.385 47.904 18.608 49.56 ;
     RECT  18.608 2.148 18.712 49.692 ;
     RECT  18.712 2.418 18.737 49.692 ;
     RECT  18.737 2.418 18.821 49.8 ;
     RECT  18.821 2.418 18.904 49.512 ;
     RECT  18.904 36.864 19.043 37.032 ;
     RECT  18.904 48.96 19.289 49.512 ;
     RECT  19.289 48.96 19.469 49.272 ;
     RECT  19.469 49.248 20.444 49.272 ;
     RECT  20.444 49.008 20.531 49.272 ;
     RECT  20.531 49.248 20.797 49.272 ;
     RECT  20.797 49.248 21.161 49.56 ;
     RECT  20.329 27.888 21.265 27.912 ;
     RECT  21.265 27.84 21.395 27.912 ;
     RECT  18.904 47.904 21.548 47.928 ;
     RECT  21.548 47.904 21.635 48.36 ;
     RECT  21.395 27.84 21.701 27.864 ;
     RECT  19.043 37.008 22.813 37.032 ;
     RECT  22.813 36.864 22.853 37.032 ;
     RECT  21.161 49.536 22.921 49.56 ;
     RECT  22.921 49.248 23.941 49.56 ;
     RECT  22.853 36.864 24.008 36.888 ;
     RECT  21.349 40.848 24.008 40.872 ;
     RECT  23.941 49.248 24.008 49.848 ;
     RECT  24.008 2.148 24.028 49.848 ;
     RECT  24.028 2.148 24.112 49.692 ;
     RECT  24.112 2.418 24.304 49.56 ;
     RECT  24.304 36.864 24.401 37.032 ;
     RECT  24.304 49.248 25.283 49.56 ;
     RECT  25.283 49.536 26.533 49.56 ;
     RECT  24.304 40.848 26.701 40.872 ;
     RECT  24.401 37.008 26.773 37.032 ;
     RECT  26.773 36.864 26.813 37.032 ;
     RECT  26.533 49.488 26.845 49.56 ;
     RECT  26.845 49.008 27.011 49.56 ;
     RECT  26.701 40.656 27.029 40.872 ;
     RECT  27.011 49.536 27.169 49.56 ;
     RECT  27.169 49.536 27.443 50.184 ;
     RECT  27.443 49.536 27.875 49.56 ;
     RECT  29.125 49.488 29.365 49.512 ;
     RECT  26.813 36.864 29.408 36.888 ;
     RECT  27.029 40.656 29.408 40.68 ;
     RECT  29.365 49.296 29.408 49.512 ;
     RECT  29.408 2.148 29.512 49.692 ;
     RECT  29.512 2.418 29.516 49.692 ;
     RECT  29.516 2.418 29.603 49.8 ;
     RECT  29.603 2.418 29.704 49.56 ;
     RECT  29.704 49.536 30.035 49.56 ;
     RECT  29.704 36.864 31.169 36.888 ;
     RECT  31.285 49.488 31.372 49.512 ;
     RECT  31.597 49.536 32.195 49.56 ;
     RECT  32.204 37.008 32.291 37.032 ;
     RECT  29.704 40.656 32.291 40.68 ;
     RECT  33.445 49.248 33.545 49.272 ;
     RECT  34.153 50.736 34.355 50.76 ;
     RECT  32.245 33.6 34.808 33.624 ;
     RECT  33.757 49.536 34.808 49.56 ;
     RECT  34.808 2.148 34.912 49.692 ;
     RECT  34.912 2.418 35.104 49.512 ;
     RECT  35.104 33.552 35.705 33.624 ;
     RECT  35.104 49.488 35.705 49.512 ;
     RECT  35.917 49.536 36.083 49.56 ;
     RECT  36.421 50.736 36.515 50.76 ;
     RECT  35.705 33.552 40.208 33.576 ;
     RECT  40.208 2.148 40.312 49.692 ;
     RECT  40.312 2.418 40.504 49.422 ;
     RECT  42.284 25.632 42.325 25.656 ;
     RECT  42.325 25.488 42.371 25.656 ;
     RECT  42.284 27.312 42.371 27.336 ;
     RECT  40.504 33.552 42.371 33.576 ;
     RECT  42.371 25.488 43.945 25.512 ;
     RECT  43.945 25.056 43.985 25.512 ;
     RECT  43.985 25.056 45.565 25.08 ;
     RECT  45.565 24.48 45.608 25.08 ;
     RECT  45.565 26.256 45.608 26.28 ;
     RECT  45.608 2.148 45.712 49.692 ;
     RECT  45.712 2.418 45.904 49.422 ;
     RECT  45.904 24.48 46.541 24.504 ;
     RECT  45.904 26.256 46.613 26.328 ;
     RECT  46.969 27.36 47.123 27.384 ;
     RECT  46.613 26.256 47.153 26.28 ;
     RECT  49.813 25.872 50.677 25.896 ;
     RECT  50.641 27.168 50.677 27.192 ;
     RECT  50.677 24.144 51.804 27.624 ;
    LAYER M5 ;
     RECT  2.4 2.137 2.52 2.151 ;
     RECT  7.8 2.137 7.92 2.151 ;
     RECT  13.2 2.137 13.32 2.151 ;
     RECT  18.6 2.137 18.72 2.151 ;
     RECT  24 2.137 24.12 2.151 ;
     RECT  29.4 2.137 29.52 2.151 ;
     RECT  34.8 2.137 34.92 2.151 ;
     RECT  40.2 2.137 40.32 2.151 ;
     RECT  45.6 2.137 45.72 2.151 ;
     RECT  47.088 26.245 47.112 27.395 ;
     RECT  2.4 2.151 2.712 30.805 ;
     RECT  2.4 30.805 2.808 32.003 ;
     RECT  42.336 25.621 42.36 33.587 ;
     RECT  2.4 32.003 2.712 35.365 ;
     RECT  2.4 35.365 2.904 35.795 ;
     RECT  18.6 2.151 18.912 36.853 ;
     RECT  18.6 36.853 19.032 37.043 ;
     RECT  32.256 33.589 32.28 40.691 ;
     RECT  21.36 27.877 21.384 40.837 ;
     RECT  21.36 40.837 21.624 40.883 ;
     RECT  21.6 40.883 21.624 48.371 ;
     RECT  15.312 36.997 15.336 48.997 ;
     RECT  24 2.151 24.312 49.237 ;
     RECT  18.6 37.043 18.912 49.477 ;
     RECT  26.976 48.997 27 49.477 ;
     RECT  29.4 2.151 29.712 49.477 ;
     RECT  34.8 2.151 35.112 49.477 ;
     RECT  15.312 48.997 15.768 49.525 ;
     RECT  17.04 49.477 17.064 49.525 ;
     RECT  18.336 49.477 19.224 49.525 ;
     RECT  20.496 48.997 20.52 49.525 ;
     RECT  24 49.237 25.272 49.525 ;
     RECT  26.544 49.477 27 49.525 ;
     RECT  29.136 49.477 29.712 49.525 ;
     RECT  31.296 49.477 31.32 49.525 ;
     RECT  33.456 49.237 33.48 49.525 ;
     RECT  34.8 49.477 35.64 49.525 ;
     RECT  2.4 35.795 2.712 49.689 ;
     RECT  7.8 2.151 8.112 49.689 ;
     RECT  13.2 2.151 13.512 49.689 ;
     RECT  40.2 2.151 40.512 49.689 ;
     RECT  45.6 2.151 45.912 49.689 ;
     RECT  2.4 49.689 2.52 49.703 ;
     RECT  7.8 49.689 7.92 49.703 ;
     RECT  13.2 49.689 13.32 49.703 ;
     RECT  33.456 49.525 36.072 49.703 ;
     RECT  40.2 49.689 40.32 49.703 ;
     RECT  45.6 49.689 45.72 49.703 ;
     RECT  33.456 49.703 33.912 50.725 ;
     RECT  35.616 49.703 36.072 50.725 ;
     RECT  15.312 49.525 19.224 51.792 ;
     RECT  20.496 49.525 21.384 51.792 ;
     RECT  22.656 49.525 27.864 51.792 ;
     RECT  29.136 49.525 30.024 51.792 ;
     RECT  31.296 49.525 32.184 51.792 ;
     RECT  33.456 50.725 34.344 51.792 ;
     RECT  35.616 50.725 36.504 51.792 ;
     RECT  45.912 26.245 47.088 27.395 ;
     RECT  21.6 48.371 21.624 48.997 ;
     RECT  20.52 48.997 21.624 49.525 ;
     RECT  33.48 49.237 34.8 49.525 ;
     RECT  15.768 49.477 17.04 49.525 ;
     RECT  17.064 49.477 18.336 49.525 ;
     RECT  19.224 49.477 20.496 51.708 ;
     RECT  25.272 49.477 26.544 49.525 ;
     RECT  21.384 49.525 22.656 51.708 ;
     RECT  27.864 49.525 29.136 51.708 ;
     RECT  30.024 49.525 31.296 51.708 ;
     RECT  32.184 49.525 33.456 51.708 ;
     RECT  33.912 49.703 35.616 50.725 ;
     RECT  34.344 50.725 35.616 51.708 ;
     RECT  19.272 51.708 19.584 51.792 ;
     RECT  19.704 51.708 20.016 51.792 ;
     RECT  20.136 51.708 20.448 51.792 ;
     RECT  21.432 51.708 21.744 51.792 ;
     RECT  21.864 51.708 22.176 51.792 ;
     RECT  22.296 51.708 22.608 51.792 ;
     RECT  27.912 51.708 28.224 51.792 ;
     RECT  28.344 51.708 28.656 51.792 ;
     RECT  28.776 51.708 29.088 51.792 ;
     RECT  30.072 51.708 30.384 51.792 ;
     RECT  30.504 51.708 30.816 51.792 ;
     RECT  30.936 51.708 31.248 51.792 ;
     RECT  32.232 51.708 32.544 51.792 ;
     RECT  32.664 51.708 32.976 51.792 ;
     RECT  33.096 51.708 33.408 51.792 ;
     RECT  34.392 51.708 34.704 51.792 ;
     RECT  34.824 51.708 35.136 51.792 ;
     RECT  35.256 51.708 35.568 51.792 ;
  END
END dsfd_vm_static_read_v0
END LIBRARY
